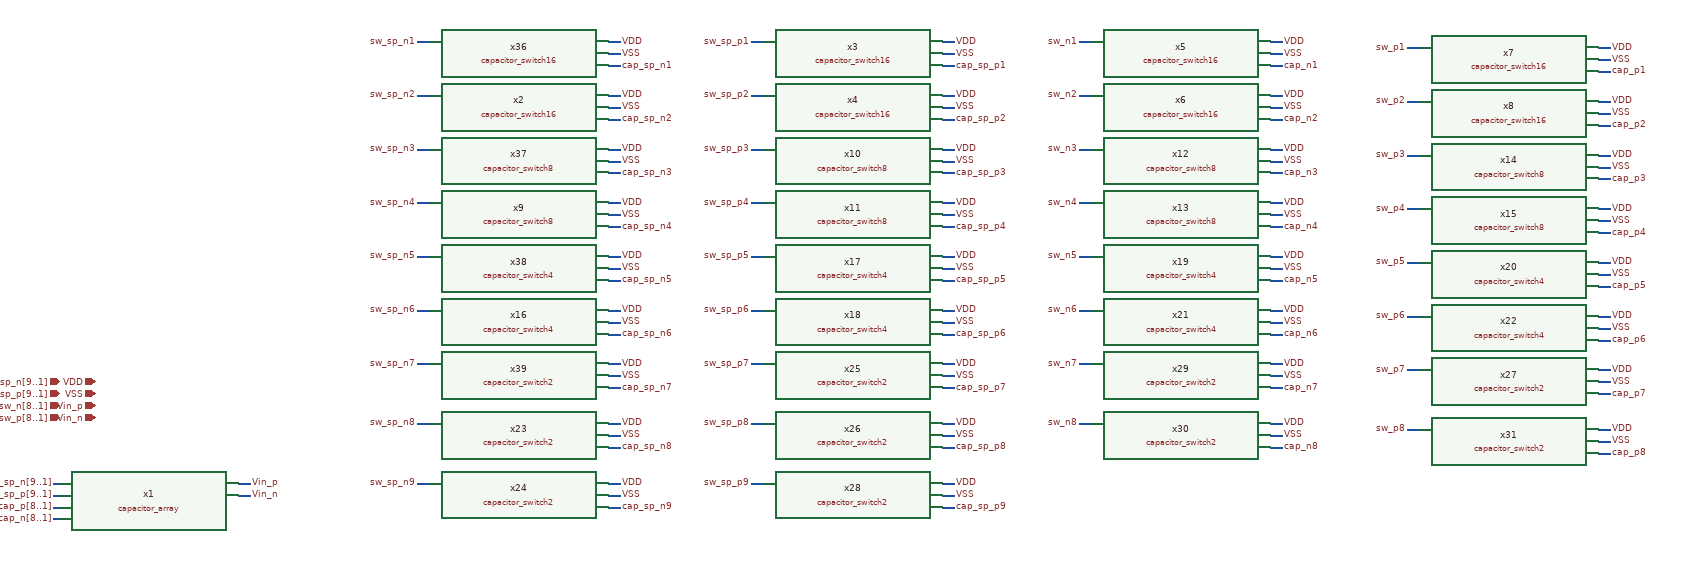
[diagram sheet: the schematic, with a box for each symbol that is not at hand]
v {xschem version=3.1.0 file_version=1.2
}
G {}
K {}
V {}
S {}
E {}
N 140 -220 150 -220 {
lab=cap_sp_n[9..1]}
N 140 -200 150 -200 {
lab=cap_sp_p[9..1]}
N 140 -180 150 -180 {
lab=cap_p[8..1]}
N 140 -160 150 -160 {
lab=cap_n[8..1]}
N 450 -220 470 -220 {
lab=Vin_p}
N 450 -200 470 -200 {
lab=Vin_n}
N 1070 -920 1090 -920 {
lab=cap_sp_n1}
N 1070 -960 1090 -960 {
lab=VDD}
N 1070 -940 1090 -940 {
lab=VSS}
N 750 -960 770 -960 {
lab=sw_sp_n1}
N 1070 -830 1090 -830 {
lab=cap_sp_n2}
N 1070 -870 1090 -870 {
lab=VDD}
N 1070 -850 1090 -850 {
lab=VSS}
N 750 -870 770 -870 {
lab=sw_sp_n2}
N 1070 -740 1090 -740 {
lab=cap_sp_n3}
N 1070 -780 1090 -780 {
lab=VDD}
N 1070 -760 1090 -760 {
lab=VSS}
N 750 -780 770 -780 {
lab=sw_sp_n3}
N 1070 -650 1090 -650 {
lab=cap_sp_n4}
N 1070 -690 1090 -690 {
lab=VDD}
N 1070 -670 1090 -670 {
lab=VSS}
N 750 -690 770 -690 {
lab=sw_sp_n4}
N 1070 -560 1090 -560 {
lab=cap_sp_n5}
N 1070 -600 1090 -600 {
lab=VDD}
N 1070 -580 1090 -580 {
lab=VSS}
N 750 -600 770 -600 {
lab=sw_sp_n5}
N 1070 -470 1090 -470 {
lab=cap_sp_n6}
N 1070 -510 1090 -510 {
lab=VDD}
N 1070 -490 1090 -490 {
lab=VSS}
N 750 -510 770 -510 {
lab=sw_sp_n6}
N 1070 -380 1090 -380 {
lab=cap_sp_n7}
N 1070 -420 1090 -420 {
lab=VDD}
N 1070 -400 1090 -400 {
lab=VSS}
N 750 -420 770 -420 {
lab=sw_sp_n7}
N 1070 -280 1090 -280 {
lab=cap_sp_n8}
N 1070 -320 1090 -320 {
lab=VDD}
N 1070 -300 1090 -300 {
lab=VSS}
N 750 -320 770 -320 {
lab=sw_sp_n8}
N 1070 -180 1090 -180 {
lab=cap_sp_n9}
N 1070 -220 1090 -220 {
lab=VDD}
N 1070 -200 1090 -200 {
lab=VSS}
N 750 -220 770 -220 {
lab=sw_sp_n9}
N 1630 -920 1650 -920 {
lab=cap_sp_p1}
N 1630 -960 1650 -960 {
lab=VDD}
N 1630 -940 1650 -940 {
lab=VSS}
N 1310 -960 1330 -960 {
lab=sw_sp_p1}
N 1630 -830 1650 -830 {
lab=cap_sp_p2}
N 1630 -870 1650 -870 {
lab=VDD}
N 1630 -850 1650 -850 {
lab=VSS}
N 1310 -870 1330 -870 {
lab=sw_sp_p2}
N 1630 -740 1650 -740 {
lab=cap_sp_p3}
N 1630 -780 1650 -780 {
lab=VDD}
N 1630 -760 1650 -760 {
lab=VSS}
N 1310 -780 1330 -780 {
lab=sw_sp_p3}
N 1630 -650 1650 -650 {
lab=cap_sp_p4}
N 1630 -690 1650 -690 {
lab=VDD}
N 1630 -670 1650 -670 {
lab=VSS}
N 1310 -690 1330 -690 {
lab=sw_sp_p4}
N 1630 -560 1650 -560 {
lab=cap_sp_p5}
N 1630 -600 1650 -600 {
lab=VDD}
N 1630 -580 1650 -580 {
lab=VSS}
N 1310 -600 1330 -600 {
lab=sw_sp_p5}
N 1630 -470 1650 -470 {
lab=cap_sp_p6}
N 1630 -510 1650 -510 {
lab=VDD}
N 1630 -490 1650 -490 {
lab=VSS}
N 1310 -510 1330 -510 {
lab=sw_sp_p6}
N 1630 -380 1650 -380 {
lab=cap_sp_p7}
N 1630 -420 1650 -420 {
lab=VDD}
N 1630 -400 1650 -400 {
lab=VSS}
N 1310 -420 1330 -420 {
lab=sw_sp_p7}
N 1630 -280 1650 -280 {
lab=cap_sp_p8}
N 1630 -320 1650 -320 {
lab=VDD}
N 1630 -300 1650 -300 {
lab=VSS}
N 1310 -320 1330 -320 {
lab=sw_sp_p8}
N 1630 -180 1650 -180 {
lab=cap_sp_p9}
N 1630 -220 1650 -220 {
lab=VDD}
N 1630 -200 1650 -200 {
lab=VSS}
N 1310 -220 1330 -220 {
lab=sw_sp_p9}
N 2730 -910 2750 -910 {
lab=cap_p1}
N 2730 -950 2750 -950 {
lab=VDD}
N 2730 -930 2750 -930 {
lab=VSS}
N 2410 -950 2430 -950 {
lab=sw_p1}
N 2730 -820 2750 -820 {
lab=cap_p2}
N 2730 -860 2750 -860 {
lab=VDD}
N 2730 -840 2750 -840 {
lab=VSS}
N 2410 -860 2430 -860 {
lab=sw_p2}
N 2730 -730 2750 -730 {
lab=cap_p3}
N 2730 -770 2750 -770 {
lab=VDD}
N 2730 -750 2750 -750 {
lab=VSS}
N 2410 -770 2430 -770 {
lab=sw_p3}
N 2730 -640 2750 -640 {
lab=cap_p4}
N 2730 -680 2750 -680 {
lab=VDD}
N 2730 -660 2750 -660 {
lab=VSS}
N 2410 -680 2430 -680 {
lab=sw_p4}
N 2730 -550 2750 -550 {
lab=cap_p5}
N 2730 -590 2750 -590 {
lab=VDD}
N 2730 -570 2750 -570 {
lab=VSS}
N 2410 -590 2430 -590 {
lab=sw_p5}
N 2730 -460 2750 -460 {
lab=cap_p6}
N 2730 -500 2750 -500 {
lab=VDD}
N 2730 -480 2750 -480 {
lab=VSS}
N 2410 -500 2430 -500 {
lab=sw_p6}
N 2730 -370 2750 -370 {
lab=cap_p7}
N 2730 -410 2750 -410 {
lab=VDD}
N 2730 -390 2750 -390 {
lab=VSS}
N 2410 -410 2430 -410 {
lab=sw_p7}
N 2730 -270 2750 -270 {
lab=cap_p8}
N 2730 -310 2750 -310 {
lab=VDD}
N 2730 -290 2750 -290 {
lab=VSS}
N 2410 -310 2430 -310 {
lab=sw_p8}
N 2180 -920 2200 -920 {
lab=cap_n1}
N 2180 -960 2200 -960 {
lab=VDD}
N 2180 -940 2200 -940 {
lab=VSS}
N 1860 -960 1880 -960 {
lab=sw_n1}
N 2180 -830 2200 -830 {
lab=cap_n2}
N 2180 -870 2200 -870 {
lab=VDD}
N 2180 -850 2200 -850 {
lab=VSS}
N 1860 -870 1880 -870 {
lab=sw_n2}
N 2180 -740 2200 -740 {
lab=cap_n3}
N 2180 -780 2200 -780 {
lab=VDD}
N 2180 -760 2200 -760 {
lab=VSS}
N 1860 -780 1880 -780 {
lab=sw_n3}
N 2180 -650 2200 -650 {
lab=cap_n4}
N 2180 -690 2200 -690 {
lab=VDD}
N 2180 -670 2200 -670 {
lab=VSS}
N 1860 -690 1880 -690 {
lab=sw_n4}
N 2180 -560 2200 -560 {
lab=cap_n5}
N 2180 -600 2200 -600 {
lab=VDD}
N 2180 -580 2200 -580 {
lab=VSS}
N 1860 -600 1880 -600 {
lab=sw_n5}
N 2180 -470 2200 -470 {
lab=cap_n6}
N 2180 -510 2200 -510 {
lab=VDD}
N 2180 -490 2200 -490 {
lab=VSS}
N 1860 -510 1880 -510 {
lab=sw_n6}
N 2180 -380 2200 -380 {
lab=cap_n7}
N 2180 -420 2200 -420 {
lab=VDD}
N 2180 -400 2200 -400 {
lab=VSS}
N 1860 -420 1880 -420 {
lab=sw_n7}
N 2180 -280 2200 -280 {
lab=cap_n8}
N 2180 -320 2200 -320 {
lab=VDD}
N 2180 -300 2200 -300 {
lab=VSS}
N 1860 -320 1880 -320 {
lab=sw_n8}
C {devices/title.sym} 160 30 0 0 {name=l1 author="Dr. Aubrey Beal, Dr. Phillip Bailey, Micah Tseng"
}
C {src/capacitor_array/capacitor_array.sym} 300 -190 0 0 {name=x1 unit_cap_w=5 unit_cap_l=5
}
C {devices/iopin.sym} 210 -390 0 0 {name=p1 lab=VDD
}
C {devices/ipin.sym} 150 -390 0 0 {name=p3 lab=sw_sp_n[9..1]
}
C {devices/iopin.sym} 210 -370 0 0 {name=p4 lab=VSS
}
C {devices/iopin.sym} 210 -350 0 0 {name=p5 lab=Vin_p
}
C {devices/iopin.sym} 210 -330 0 0 {name=p6 lab=Vin_n
}
C {devices/ipin.sym} 150 -370 0 0 {name=p2 lab=sw_sp_p[9..1]
}
C {devices/ipin.sym} 150 -350 0 0 {name=p7 lab=sw_n[8..1]
}
C {devices/ipin.sym} 150 -330 0 0 {name=p8 lab=sw_p[8..1]
}
C {devices/lab_pin.sym} 140 -220 0 0 {name=l2 sig_type=std_logic lab=cap_sp_n[9..1]
}
C {devices/lab_pin.sym} 140 -200 0 0 {name=l3 sig_type=std_logic lab=cap_sp_p[9..1]
}
C {devices/lab_pin.sym} 140 -180 0 0 {name=l4 sig_type=std_logic lab=cap_p[8..1]
}
C {devices/lab_pin.sym} 140 -160 0 0 {name=l5 sig_type=std_logic lab=cap_n[8..1]
}
C {devices/lab_pin.sym} 470 -220 2 0 {name=l6 sig_type=std_logic lab=Vin_p
}
C {devices/lab_pin.sym} 470 -200 2 0 {name=l7 sig_type=std_logic lab=Vin_n
}
C {devices/lab_pin.sym} 1090 -920 2 0 {name=l8 sig_type=std_logic lab=cap_sp_n1
}
C {devices/lab_pin.sym} 1090 -960 2 0 {name=l9 sig_type=std_logic lab=VDD
}
C {devices/lab_pin.sym} 1090 -940 2 0 {name=l10 sig_type=std_logic lab=VSS
}
C {devices/lab_pin.sym} 750 -960 0 0 {name=l11 sig_type=std_logic lab=sw_sp_n1
}
C {devices/lab_pin.sym} 1090 -830 2 0 {name=l12 sig_type=std_logic lab=cap_sp_n2
}
C {devices/lab_pin.sym} 1090 -870 2 0 {name=l13 sig_type=std_logic lab=VDD
}
C {devices/lab_pin.sym} 1090 -850 2 0 {name=l14 sig_type=std_logic lab=VSS
}
C {devices/lab_pin.sym} 750 -870 0 0 {name=l15 sig_type=std_logic lab=sw_sp_n2
}
C {devices/lab_pin.sym} 1090 -740 2 0 {name=l16 sig_type=std_logic lab=cap_sp_n3
}
C {devices/lab_pin.sym} 1090 -780 2 0 {name=l17 sig_type=std_logic lab=VDD
}
C {devices/lab_pin.sym} 1090 -760 2 0 {name=l18 sig_type=std_logic lab=VSS
}
C {devices/lab_pin.sym} 750 -780 0 0 {name=l19 sig_type=std_logic lab=sw_sp_n3
}
C {devices/lab_pin.sym} 1090 -650 2 0 {name=l20 sig_type=std_logic lab=cap_sp_n4
}
C {devices/lab_pin.sym} 1090 -690 2 0 {name=l21 sig_type=std_logic lab=VDD
}
C {devices/lab_pin.sym} 1090 -670 2 0 {name=l22 sig_type=std_logic lab=VSS
}
C {devices/lab_pin.sym} 750 -690 0 0 {name=l23 sig_type=std_logic lab=sw_sp_n4
}
C {devices/lab_pin.sym} 1090 -560 2 0 {name=l24 sig_type=std_logic lab=cap_sp_n5
}
C {devices/lab_pin.sym} 1090 -600 2 0 {name=l25 sig_type=std_logic lab=VDD
}
C {devices/lab_pin.sym} 1090 -580 2 0 {name=l26 sig_type=std_logic lab=VSS
}
C {devices/lab_pin.sym} 750 -600 0 0 {name=l27 sig_type=std_logic lab=sw_sp_n5
}
C {devices/lab_pin.sym} 1090 -470 2 0 {name=l28 sig_type=std_logic lab=cap_sp_n6
}
C {devices/lab_pin.sym} 1090 -510 2 0 {name=l29 sig_type=std_logic lab=VDD
}
C {devices/lab_pin.sym} 1090 -490 2 0 {name=l30 sig_type=std_logic lab=VSS
}
C {devices/lab_pin.sym} 750 -510 0 0 {name=l31 sig_type=std_logic lab=sw_sp_n6
}
C {devices/lab_pin.sym} 1090 -380 2 0 {name=l32 sig_type=std_logic lab=cap_sp_n7
}
C {devices/lab_pin.sym} 1090 -420 2 0 {name=l33 sig_type=std_logic lab=VDD
}
C {devices/lab_pin.sym} 1090 -400 2 0 {name=l34 sig_type=std_logic lab=VSS
}
C {devices/lab_pin.sym} 750 -420 0 0 {name=l35 sig_type=std_logic lab=sw_sp_n7
}
C {devices/lab_pin.sym} 1090 -280 2 0 {name=l36 sig_type=std_logic lab=cap_sp_n8
}
C {devices/lab_pin.sym} 1090 -320 2 0 {name=l37 sig_type=std_logic lab=VDD
}
C {devices/lab_pin.sym} 1090 -300 2 0 {name=l38 sig_type=std_logic lab=VSS
}
C {devices/lab_pin.sym} 750 -320 0 0 {name=l39 sig_type=std_logic lab=sw_sp_n8
}
C {devices/lab_pin.sym} 1090 -180 2 0 {name=l40 sig_type=std_logic lab=cap_sp_n9
}
C {devices/lab_pin.sym} 1090 -220 2 0 {name=l41 sig_type=std_logic lab=VDD
}
C {devices/lab_pin.sym} 1090 -200 2 0 {name=l42 sig_type=std_logic lab=VSS
}
C {devices/lab_pin.sym} 750 -220 0 0 {name=l43 sig_type=std_logic lab=sw_sp_n9
}
C {devices/lab_pin.sym} 1650 -920 2 0 {name=l44 sig_type=std_logic lab=cap_sp_p1
}
C {devices/lab_pin.sym} 1650 -960 2 0 {name=l45 sig_type=std_logic lab=VDD
}
C {devices/lab_pin.sym} 1650 -940 2 0 {name=l46 sig_type=std_logic lab=VSS
}
C {devices/lab_pin.sym} 1310 -960 0 0 {name=l47 sig_type=std_logic lab=sw_sp_p1
}
C {devices/lab_pin.sym} 1650 -830 2 0 {name=l48 sig_type=std_logic lab=cap_sp_p2
}
C {devices/lab_pin.sym} 1650 -870 2 0 {name=l49 sig_type=std_logic lab=VDD
}
C {devices/lab_pin.sym} 1650 -850 2 0 {name=l50 sig_type=std_logic lab=VSS
}
C {devices/lab_pin.sym} 1310 -870 0 0 {name=l51 sig_type=std_logic lab=sw_sp_p2
}
C {devices/lab_pin.sym} 1650 -740 2 0 {name=l52 sig_type=std_logic lab=cap_sp_p3
}
C {devices/lab_pin.sym} 1650 -780 2 0 {name=l53 sig_type=std_logic lab=VDD
}
C {devices/lab_pin.sym} 1650 -760 2 0 {name=l54 sig_type=std_logic lab=VSS
}
C {devices/lab_pin.sym} 1310 -780 0 0 {name=l55 sig_type=std_logic lab=sw_sp_p3
}
C {devices/lab_pin.sym} 1650 -650 2 0 {name=l56 sig_type=std_logic lab=cap_sp_p4
}
C {devices/lab_pin.sym} 1650 -690 2 0 {name=l57 sig_type=std_logic lab=VDD
}
C {devices/lab_pin.sym} 1650 -670 2 0 {name=l58 sig_type=std_logic lab=VSS
}
C {devices/lab_pin.sym} 1310 -690 0 0 {name=l59 sig_type=std_logic lab=sw_sp_p4
}
C {devices/lab_pin.sym} 1650 -560 2 0 {name=l60 sig_type=std_logic lab=cap_sp_p5
}
C {devices/lab_pin.sym} 1650 -600 2 0 {name=l61 sig_type=std_logic lab=VDD
}
C {devices/lab_pin.sym} 1650 -580 2 0 {name=l62 sig_type=std_logic lab=VSS
}
C {devices/lab_pin.sym} 1310 -600 0 0 {name=l63 sig_type=std_logic lab=sw_sp_p5
}
C {devices/lab_pin.sym} 1650 -470 2 0 {name=l64 sig_type=std_logic lab=cap_sp_p6
}
C {devices/lab_pin.sym} 1650 -510 2 0 {name=l65 sig_type=std_logic lab=VDD
}
C {devices/lab_pin.sym} 1650 -490 2 0 {name=l66 sig_type=std_logic lab=VSS
}
C {devices/lab_pin.sym} 1310 -510 0 0 {name=l67 sig_type=std_logic lab=sw_sp_p6
}
C {devices/lab_pin.sym} 1650 -380 2 0 {name=l68 sig_type=std_logic lab=cap_sp_p7
}
C {devices/lab_pin.sym} 1650 -420 2 0 {name=l69 sig_type=std_logic lab=VDD
}
C {devices/lab_pin.sym} 1650 -400 2 0 {name=l70 sig_type=std_logic lab=VSS
}
C {devices/lab_pin.sym} 1310 -420 0 0 {name=l71 sig_type=std_logic lab=sw_sp_p7
}
C {devices/lab_pin.sym} 1650 -280 2 0 {name=l72 sig_type=std_logic lab=cap_sp_p8
}
C {devices/lab_pin.sym} 1650 -320 2 0 {name=l73 sig_type=std_logic lab=VDD
}
C {devices/lab_pin.sym} 1650 -300 2 0 {name=l74 sig_type=std_logic lab=VSS
}
C {devices/lab_pin.sym} 1310 -320 0 0 {name=l75 sig_type=std_logic lab=sw_sp_p8
}
C {devices/lab_pin.sym} 1650 -180 2 0 {name=l76 sig_type=std_logic lab=cap_sp_p9
}
C {devices/lab_pin.sym} 1650 -220 2 0 {name=l77 sig_type=std_logic lab=VDD
}
C {devices/lab_pin.sym} 1650 -200 2 0 {name=l78 sig_type=std_logic lab=VSS
}
C {devices/lab_pin.sym} 1310 -220 0 0 {name=l79 sig_type=std_logic lab=sw_sp_p9
}
C {devices/lab_pin.sym} 2750 -910 2 0 {name=l80 sig_type=std_logic lab=cap_p1
}
C {devices/lab_pin.sym} 2750 -950 2 0 {name=l81 sig_type=std_logic lab=VDD
}
C {devices/lab_pin.sym} 2750 -930 2 0 {name=l82 sig_type=std_logic lab=VSS
}
C {devices/lab_pin.sym} 2410 -950 0 0 {name=l83 sig_type=std_logic lab=sw_p1
}
C {devices/lab_pin.sym} 2750 -820 2 0 {name=l84 sig_type=std_logic lab=cap_p2
}
C {devices/lab_pin.sym} 2750 -860 2 0 {name=l85 sig_type=std_logic lab=VDD
}
C {devices/lab_pin.sym} 2750 -840 2 0 {name=l86 sig_type=std_logic lab=VSS
}
C {devices/lab_pin.sym} 2410 -860 0 0 {name=l87 sig_type=std_logic lab=sw_p2
}
C {devices/lab_pin.sym} 2750 -730 2 0 {name=l88 sig_type=std_logic lab=cap_p3
}
C {devices/lab_pin.sym} 2750 -770 2 0 {name=l89 sig_type=std_logic lab=VDD
}
C {devices/lab_pin.sym} 2750 -750 2 0 {name=l90 sig_type=std_logic lab=VSS
}
C {devices/lab_pin.sym} 2410 -770 0 0 {name=l91 sig_type=std_logic lab=sw_p3
}
C {devices/lab_pin.sym} 2750 -640 2 0 {name=l92 sig_type=std_logic lab=cap_p4
}
C {devices/lab_pin.sym} 2750 -680 2 0 {name=l93 sig_type=std_logic lab=VDD
}
C {devices/lab_pin.sym} 2750 -660 2 0 {name=l94 sig_type=std_logic lab=VSS
}
C {devices/lab_pin.sym} 2410 -680 0 0 {name=l95 sig_type=std_logic lab=sw_p4
}
C {devices/lab_pin.sym} 2750 -550 2 0 {name=l96 sig_type=std_logic lab=cap_p5
}
C {devices/lab_pin.sym} 2750 -590 2 0 {name=l97 sig_type=std_logic lab=VDD
}
C {devices/lab_pin.sym} 2750 -570 2 0 {name=l98 sig_type=std_logic lab=VSS
}
C {devices/lab_pin.sym} 2410 -590 0 0 {name=l99 sig_type=std_logic lab=sw_p5
}
C {devices/lab_pin.sym} 2750 -460 2 0 {name=l100 sig_type=std_logic lab=cap_p6
}
C {devices/lab_pin.sym} 2750 -500 2 0 {name=l101 sig_type=std_logic lab=VDD
}
C {devices/lab_pin.sym} 2750 -480 2 0 {name=l102 sig_type=std_logic lab=VSS
}
C {devices/lab_pin.sym} 2410 -500 0 0 {name=l103 sig_type=std_logic lab=sw_p6
}
C {devices/lab_pin.sym} 2750 -370 2 0 {name=l104 sig_type=std_logic lab=cap_p7
}
C {devices/lab_pin.sym} 2750 -410 2 0 {name=l105 sig_type=std_logic lab=VDD
}
C {devices/lab_pin.sym} 2750 -390 2 0 {name=l106 sig_type=std_logic lab=VSS
}
C {devices/lab_pin.sym} 2410 -410 0 0 {name=l107 sig_type=std_logic lab=sw_p7
}
C {devices/lab_pin.sym} 2750 -270 2 0 {name=l108 sig_type=std_logic lab=cap_p8
}
C {devices/lab_pin.sym} 2750 -310 2 0 {name=l109 sig_type=std_logic lab=VDD
}
C {devices/lab_pin.sym} 2750 -290 2 0 {name=l110 sig_type=std_logic lab=VSS
}
C {devices/lab_pin.sym} 2410 -310 0 0 {name=l111 sig_type=std_logic lab=sw_p8
}
C {devices/lab_pin.sym} 2200 -920 2 0 {name=l112 sig_type=std_logic lab=cap_n1
}
C {devices/lab_pin.sym} 2200 -960 2 0 {name=l113 sig_type=std_logic lab=VDD
}
C {devices/lab_pin.sym} 2200 -940 2 0 {name=l114 sig_type=std_logic lab=VSS
}
C {devices/lab_pin.sym} 1860 -960 0 0 {name=l115 sig_type=std_logic lab=sw_n1
}
C {devices/lab_pin.sym} 2200 -830 2 0 {name=l116 sig_type=std_logic lab=cap_n2
}
C {devices/lab_pin.sym} 2200 -870 2 0 {name=l117 sig_type=std_logic lab=VDD
}
C {devices/lab_pin.sym} 2200 -850 2 0 {name=l118 sig_type=std_logic lab=VSS
}
C {devices/lab_pin.sym} 1860 -870 0 0 {name=l119 sig_type=std_logic lab=sw_n2
}
C {devices/lab_pin.sym} 2200 -740 2 0 {name=l120 sig_type=std_logic lab=cap_n3
}
C {devices/lab_pin.sym} 2200 -780 2 0 {name=l121 sig_type=std_logic lab=VDD
}
C {devices/lab_pin.sym} 2200 -760 2 0 {name=l122 sig_type=std_logic lab=VSS
}
C {devices/lab_pin.sym} 1860 -780 0 0 {name=l123 sig_type=std_logic lab=sw_n3
}
C {devices/lab_pin.sym} 2200 -650 2 0 {name=l124 sig_type=std_logic lab=cap_n4
}
C {devices/lab_pin.sym} 2200 -690 2 0 {name=l125 sig_type=std_logic lab=VDD
}
C {devices/lab_pin.sym} 2200 -670 2 0 {name=l126 sig_type=std_logic lab=VSS
}
C {devices/lab_pin.sym} 1860 -690 0 0 {name=l127 sig_type=std_logic lab=sw_n4
}
C {devices/lab_pin.sym} 2200 -560 2 0 {name=l128 sig_type=std_logic lab=cap_n5
}
C {devices/lab_pin.sym} 2200 -600 2 0 {name=l129 sig_type=std_logic lab=VDD
}
C {devices/lab_pin.sym} 2200 -580 2 0 {name=l130 sig_type=std_logic lab=VSS
}
C {devices/lab_pin.sym} 1860 -600 0 0 {name=l131 sig_type=std_logic lab=sw_n5
}
C {devices/lab_pin.sym} 2200 -470 2 0 {name=l132 sig_type=std_logic lab=cap_n6
}
C {devices/lab_pin.sym} 2200 -510 2 0 {name=l133 sig_type=std_logic lab=VDD
}
C {devices/lab_pin.sym} 2200 -490 2 0 {name=l134 sig_type=std_logic lab=VSS
}
C {devices/lab_pin.sym} 1860 -510 0 0 {name=l135 sig_type=std_logic lab=sw_n6
}
C {devices/lab_pin.sym} 2200 -380 2 0 {name=l136 sig_type=std_logic lab=cap_n7
}
C {devices/lab_pin.sym} 2200 -420 2 0 {name=l137 sig_type=std_logic lab=VDD
}
C {devices/lab_pin.sym} 2200 -400 2 0 {name=l138 sig_type=std_logic lab=VSS
}
C {devices/lab_pin.sym} 1860 -420 0 0 {name=l139 sig_type=std_logic lab=sw_n7
}
C {devices/lab_pin.sym} 2200 -280 2 0 {name=l140 sig_type=std_logic lab=cap_n8
}
C {devices/lab_pin.sym} 2200 -320 2 0 {name=l141 sig_type=std_logic lab=VDD
}
C {devices/lab_pin.sym} 2200 -300 2 0 {name=l142 sig_type=std_logic lab=VSS
}
C {devices/lab_pin.sym} 1860 -320 0 0 {name=l143 sig_type=std_logic lab=sw_n8
}
C {src/capacitor_switch16/capacitor_switch16.sym} 920 -940 0 0 {name=x36}
C {src/capacitor_switch8/capacitor_switch8.sym} 920 -760 0 0 {name=x37}
C {src/capacitor_switch4/capacitor_switch4.sym} 920 -580 0 0 {name=x38}
C {src/capacitor_switch2/capacitor_switch2.sym} 920 -400 0 0 {name=x39}
C {src/capacitor_switch16/capacitor_switch16.sym} 920 -850 0 0 {name=x2}
C {src/capacitor_switch16/capacitor_switch16.sym} 1480 -940 0 0 {name=x3}
C {src/capacitor_switch16/capacitor_switch16.sym} 1480 -850 0 0 {name=x4}
C {src/capacitor_switch16/capacitor_switch16.sym} 2030 -940 0 0 {name=x5}
C {src/capacitor_switch16/capacitor_switch16.sym} 2030 -850 0 0 {name=x6}
C {src/capacitor_switch16/capacitor_switch16.sym} 2580 -930 0 0 {name=x7}
C {src/capacitor_switch16/capacitor_switch16.sym} 2580 -840 0 0 {name=x8}
C {src/capacitor_switch8/capacitor_switch8.sym} 920 -670 0 0 {name=x9}
C {src/capacitor_switch8/capacitor_switch8.sym} 1480 -760 0 0 {name=x10}
C {src/capacitor_switch8/capacitor_switch8.sym} 1480 -670 0 0 {name=x11}
C {src/capacitor_switch8/capacitor_switch8.sym} 2030 -760 0 0 {name=x12}
C {src/capacitor_switch8/capacitor_switch8.sym} 2030 -670 0 0 {name=x13}
C {src/capacitor_switch8/capacitor_switch8.sym} 2580 -750 0 0 {name=x14}
C {src/capacitor_switch8/capacitor_switch8.sym} 2580 -660 0 0 {name=x15}
C {src/capacitor_switch4/capacitor_switch4.sym} 920 -490 0 0 {name=x16}
C {src/capacitor_switch4/capacitor_switch4.sym} 1480 -580 0 0 {name=x17}
C {src/capacitor_switch4/capacitor_switch4.sym} 1480 -490 0 0 {name=x18}
C {src/capacitor_switch4/capacitor_switch4.sym} 2030 -580 0 0 {name=x19}
C {src/capacitor_switch4/capacitor_switch4.sym} 2580 -570 0 0 {name=x20}
C {src/capacitor_switch4/capacitor_switch4.sym} 2030 -490 0 0 {name=x21}
C {src/capacitor_switch4/capacitor_switch4.sym} 2580 -480 0 0 {name=x22}
C {src/capacitor_switch2/capacitor_switch2.sym} 920 -300 0 0 {name=x23}
C {src/capacitor_switch2/capacitor_switch2.sym} 920 -200 0 0 {name=x24}
C {src/capacitor_switch2/capacitor_switch2.sym} 1480 -400 0 0 {name=x25}
C {src/capacitor_switch2/capacitor_switch2.sym} 1480 -300 0 0 {name=x26}
C {src/capacitor_switch2/capacitor_switch2.sym} 1480 -200 0 0 {name=x28}
C {src/capacitor_switch2/capacitor_switch2.sym} 2030 -400 0 0 {name=x29}
C {src/capacitor_switch2/capacitor_switch2.sym} 2030 -300 0 0 {name=x30}
C {src/capacitor_switch2/capacitor_switch2.sym} 2580 -390 0 0 {name=x27}
C {src/capacitor_switch2/capacitor_switch2.sym} 2580 -290 0 0 {name=x31}
